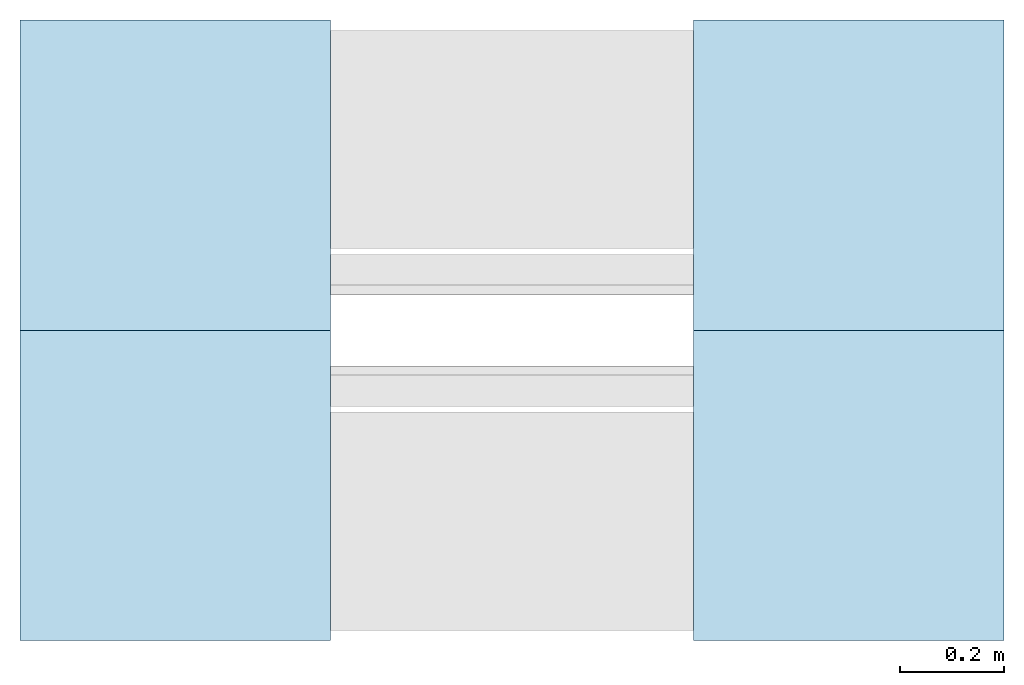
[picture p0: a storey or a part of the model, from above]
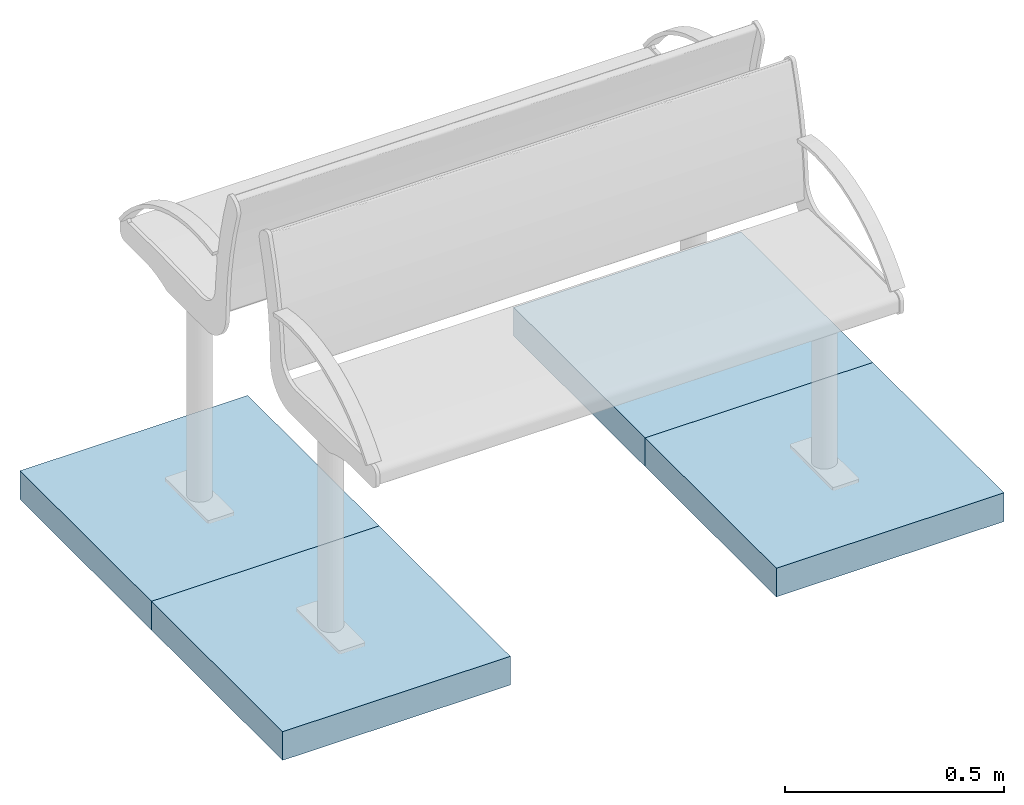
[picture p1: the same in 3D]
Properties of the parts of a building model (IFC4)

# File
Description: ViewDefinition [CoordinationView_V2.0], RevitIdentifiers [ContentGUID: d3ba7735-4996-4f2e-a220-48985317c84a, VersionGUID: 44f114b8-652d-4e34-88d7-4fcb713364eb, NumberOfSaves: 366]
File name: DB_Sitzbank_Remissio_Drahtgitter_3+3er_fest.ifc
Time: 2026-05-19T18:06:39+01:00
Written by: ODA SDAI 24.6
Made in: Autodesk Revit 24.3.40.26 (DEU) - IFC 24.3.20.0

# IfcSite, Default
RefLatitude: 42, 24, 53, 508911; RefLongitude: -71, -15, -29, -58837; RefElevation: 0 m
Pset_SiteCommon - Reference: Projektinformationen

# IfcBuilding
Pset_BuildingCommon - Reference: Projektinformationen; NumberOfStoreys: 1
Pset_BuildingElementProxyCommon - Reference: Projektinformationen; IsExternal: no
Pset_BuildingStoreyCommon - Reference: Projektinformationen; sets with these values: 2

# IfcBuildingStorey: Ebene:Ebene, DB_Bezugshoehe_max_Bahnsteigkante
LongName: DB_Bezugshoehe_max_Bahnsteigkante; Elevation: 0 m
Pset_BuildingStoreyCommon - Reference: Ebene

# IfcBuildingStorey: Ebene:Hilfsebene PU, Ebene 0
LongName: Ebene 0; Elevation: 0 m
Pset_BuildingStoreyCommon - Reference: Hilfsebene PU

# IfcBuildingElementProxy: DB_Sitzbank_Remissio_Drahtgitter_3+3er_fest:DB_Sitzbank_Remissio_Drahtgitter_3+3er_fest, DB_Sitzbank_Remissio_Drahtgitter_3+3er_fest:DB_Sitzbank_Remissio_Drahtgitter_3+3er_fest:5065
In: DB_Bezugshoehe_max_Bahnsteigkante
Type - Material: DB_Drahtgitter, DB_Stahl_pulverbeschichtet_RAL9006
Pset_BuildingElementProxyCommon - Reference: DB_Sitzbank_Remissio_Drahtgitter_3+3er_fest; IsExternal: yes
Pset_EnvironmentalImpactIndicators - Reference: DB_Sitzbank_Remissio_Drahtgitter_3+3er_fest
DB - DBAnlagentyp: Sitzmobiliar; Objekt: DB Sitzbank Remissio Drahtgitter 3+3er fest; Objektklasse: Sitzbank

# IfcSlab: DB_Sitzbank_Fundament:DB_Sitzbank_Fundament (4)
In: DB_Bezugshoehe_max_Bahnsteigkante
Type - PredefinedType: BASESLAB; Material: DB_Fertigbeton
Pset_EnvironmentalImpactIndicators - Reference: DB_Sitzbank_Fundament; sets with these values: 2
Pset_SlabCommon - Reference: DB_Sitzbank_Fundament; IsExternal: no
DB - Objekt: DB Sitzbank Remissio Drahtgitter 3+3er fest; Objektklasse: Sitzbank
Name (DB_Sitzbank_Fundament:DB_Sitzbank_Fundament:...)
23035925
23035926
23035927
23035928
